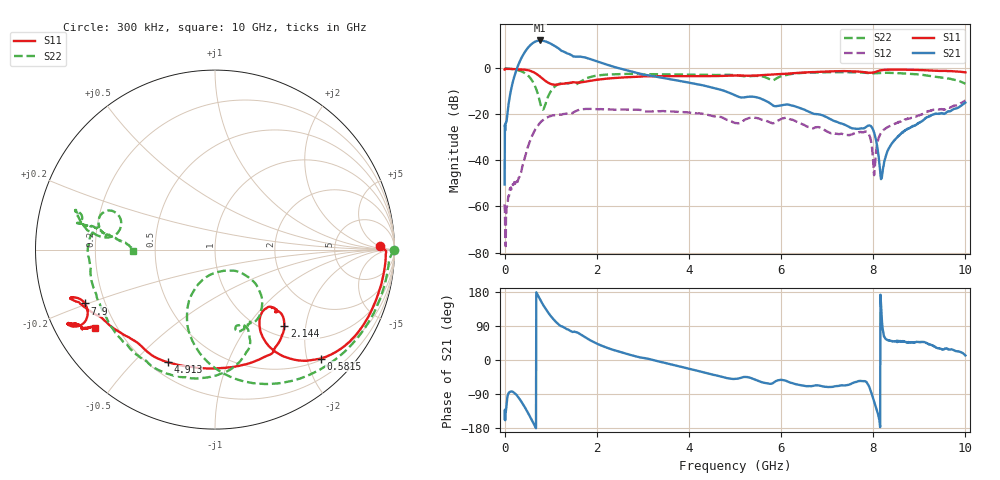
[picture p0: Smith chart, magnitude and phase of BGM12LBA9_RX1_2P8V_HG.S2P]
!Agilent Technologies,E5071C,MY46316587,B.13.01
!Date: Tue Sep 12 11:05:29 2017
!Data & Calibration Information:
!Freq	S11:SOLT2(ON)	S21:SOLT2(ON)	S12:SOLT2(ON)	S22:SOLT2(ON)
!PortZ  Port1:50+j0  Port2:50+j0
!Above PortZ is port z conversion or system Z0 setting when saving the data.
!When reading, reference impedance value at option line is always used.
# Hz S dB R 50
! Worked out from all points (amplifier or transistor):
!   1601 points, 300 kHz to 10 GHz, reference 50 ohm
!   highest |S21| = 11.9 dB at 775.3 MHz (marker M1)
!   |S21| within 3 dB of that: 513.9 MHz to 1.137 GHz (622.7 MHz wide, 75.5 % of centre)
!   unconditionally stable (mu >= 1): start of sweep to end of sweep
!   at 1.663 GHz: K = 1.54, MAG = 7.0 dB, |S12| = -18.0 dB
!   at 5 GHz: K = 8.68, MAG = -6.4 dB, |S12| = -23.9 dB
!   at 10 GHz: K = 3.77, MAG = -9.1 dB, |S12| = -14.2 dB
!   lowest NFmin = 0.69 dB at 950 MHz
!   S11 on the Smith chart (normalised r, x): 300 kHz: 22, +6; 581.5 MHz: 0.53, -2.26; 2.144 GHz: 1.20, -1.52; 4.913 GHz: 0.27, -0.63; 7.9 GHz: 0.12, -0.20; 10 GHz: 0.12, -0.29
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300000  -0.73 1.2  -50.52 -155.6  -59.07 -164.3  -0.04 -0.1
5.654831e7  -0.43 -4.0  -20.73 -101.6  -58.70 104.4  -0.29 -9.6
1.065468e8  -0.45 -7.6  -13.08 -84.9  -53.60 95.6  -0.37 -17.8
3.127906e8  -0.59 -22.5  2.03 -100.8  -47.46 130.4  -1.14 -52.0
4.627861e8  -0.85 -34.8  7.56 -129.7  -37.09 162.7  -2.57 -78.8
5.815326e8  -1.46 -45.9  10.26 -156.4  -30.05 152.7  -5.04 -100.6
6.815296e8  -2.49 -54.6  11.50 -179.9  -26.20 137.6  -8.93 -115.3
7.752768e8  -3.87 -60.1  11.87 158.6  -23.65 122.4  -15.38 -110.0
8.877734e8  -5.67 -60.9  11.46 135.6  -21.81 105.1  -15.65 -46.0
1.01277e9  -7.03 -55.1  10.34 114.3  -20.78 89.3  -9.84 -41.7
1.219013e9  -6.95 -45.4  7.67 89.5  -20.26 72.2  -6.76 -62.3
1.669e9  -6.25 -44.5  4.76 65.9  -17.96 52.0  -5.70 -68.4
2.143986e9  -4.82 -47.8  1.91 36.0  -17.89 29.5  -3.01 -91.2
3.3377e9  -3.62 -66.9  -3.99 -3.6  -18.79 4.5  -2.77 -130.6
4.912653e9  -3.35 -112.8  -11.08 -49.5  -23.07 -19.6  -3.06 176.4
5.00015e9  -3.30 -116.7  -11.91 -50.0  -23.86 -14.5  -3.15 173.3
6.66885e9  -1.84 -158.1  -19.52 -69.1  -26.08 -21.5  -2.02 165.0
7.900063e9  -2.09 -157.6  -24.96 -67.3  -28.57 -21.9  -2.30 165.5
8.025059e9  -1.89 -152.3  -28.38 -111.9  -45.71 -173.5  -2.34 168.0
8.175055e9  -1.02 -151.2  -47.98 131.7  -27.95 81.5  -2.16 169.2
8.33755e9  -0.76 -152.7  -34.87 51.7  -25.39 66.6  -2.15 169.0
1e10  -1.94 -147.1  -15.02 11.9  -14.18 17.3  -6.81 -179.1
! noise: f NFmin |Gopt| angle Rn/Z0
6.5e+08  0.7515  0.4246  39.81  0.245
7e+08  0.7427  0.3671  40.05  0.1941
7.5e+08  0.7261  0.4508  42.1  0.1868
8e+08  0.7134  0.4509  45.39  0.2423
8.5e+08  0.7065  0.4345  43.76  0.1691
9e+08  0.6886  0.449  47.74  0.1736
9.5e+08  0.6857  0.4362  48.14  0.1729
1e+09  0.6956  0.4349  50.46  0.1728
